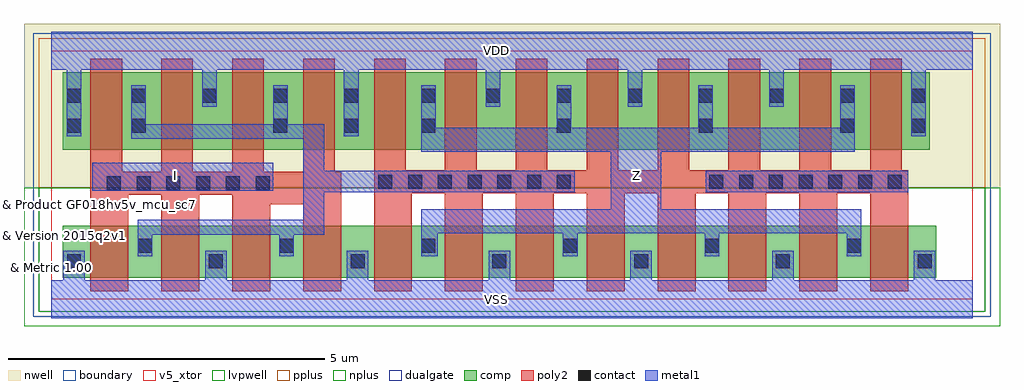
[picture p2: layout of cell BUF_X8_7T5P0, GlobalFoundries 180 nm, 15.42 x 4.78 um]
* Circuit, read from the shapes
.subckt BUF_X8_7T5P0 I VDD VSS Z
XM1 n1 I VSS VSUBS nfet_05v0 w=0.82u l=0.6u m=4
XM2 Z n1 VSS VSUBS nfet_05v0 w=0.82u l=0.6u m=8
XM3 n1 I VDD n2 pfet_05v0 w=1.22u l=0.5u m=4
XM4 Z n1 VDD n2 pfet_05v0 w=1.22u l=0.5u m=8
.ends

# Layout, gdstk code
import gdstk
lib = gdstk.Library(unit=1e-6, precision=1e-09)
def R(c, l, rs):  # rectangles x0, y0, x1, y1
    for r in rs: c.add(gdstk.rectangle(r[:2], r[2:], *l))
def A(c, l, x, y, w, h, nx, ny, dx, dy):  # array of equal rectangles
    R(c, l, [(x+i*dx, y+j*dy, x+i*dx+w, y+j*dy+h) for i in range(nx) for j in range(ny)])
def P(c, l, *ps):  # polygons
    for p in ps: c.add(gdstk.Polygon(p, *l))
boundary = (0, 0)
nwell = (21, 0)
comp = (22, 0)
poly2 = (30, 0)
pplus = (31, 0)
nplus = (32, 0)
contact = (33, 0)
metal1 = (34, 0)
dualgate = (55, 0)
v5_xtor = (112, 1)
lvpwell = (204, 0)

buf_x8_7t5p0 = lib.new_cell('BUF_X8_7T5P0')
R(buf_x8_7t5p0, boundary, [(0,0,14.56,3.92)])
R(buf_x8_7t5p0, nwell, [(-0.43,1.76,14.99,4.35)])
R(buf_x8_7t5p0, comp, [(0.18,0.34,13.98,1.16), (0.18,2.36,13.88,3.58)])
P(buf_x8_7t5p0, poly2, [(0.62,0.12),(1.22,0.12),(1.22,1.65),(1.74,1.65),(1.74,0.12),(2.34,0.12),(2.34,1.65),(2.86,1.65),(2.86,0.12),(3.46,0.12),(3.46,1.5),(3.98,1.5),(3.98,0.12),(4.58,0.12),(4.58,2.01),(4.48,2.01),(4.48,3.8),(3.98,3.8),(3.98,2.01),(3.36,2.01),(3.36,3.8),(2.86,3.8),(2.86,2.01),(2.24,2.01),(2.24,3.8),(1.74,3.8),(1.74,2.01),(1.12,2.01),(1.12,3.8),(0.62,3.8)],
  [(5.1,0.12),(5.7,0.12),(5.7,1.675),(6.22,1.675),(6.22,0.12),(6.82,0.12),(6.82,1.675),(7.34,1.675),(7.34,0.12),(7.94,0.12),(7.94,1.675),(8.46,1.675),(8.46,0.12),(9.06,0.12),(9.06,1.675),(9.58,1.675),(9.58,0.12),(10.18,0.12),(10.18,1.675),(10.7,1.675),(10.7,0.12),(11.3,0.12),(11.3,1.675),(11.82,1.675),(11.82,0.12),(12.42,0.12),(12.42,1.675),(12.94,1.675),(12.94,0.12),(13.54,0.12),(13.54,2.035),(13.44,2.035),(13.44,3.8),(12.94,3.8),(12.94,2.035),(12.32,2.035),(12.32,3.8),(11.82,3.8),(11.82,2.035),(11.2,2.035),(11.2,3.8),(10.7,3.8),(10.7,2.035),(10.08,2.035),(10.08,3.8),(9.58,3.8),(9.58,2.035),(8.96,2.035),(8.96,3.8),(8.46,3.8),(8.46,2.035),(7.84,2.035),(7.84,3.8),(7.34,3.8),(7.34,2.035),(6.72,2.035),(6.72,3.8),(6.22,3.8),(6.22,2.035),(5.6,2.035),(5.6,3.8),(5.1,3.8)])
R(buf_x8_7t5p0, pplus, [(-0.2,1.76,14.76,4.12)])
R(buf_x8_7t5p0, nplus, [(-0.2,-0.2,14.76,1.76)])
A(buf_x8_7t5p0, contact, 0.25, 0.485, 0.22, 0.22, 7, 1, 2.24, 0)
A(buf_x8_7t5p0, contact, 1.37, 0.735, 0.22, 0.22, 6, 1, 2.24, 0)
A(buf_x8_7t5p0, contact, 0.88, 1.72, 0.22, 0.22, 6, 1, 0.47, 0)
A(buf_x8_7t5p0, contact, 5.17, 1.745, 0.22, 0.22, 7, 1, 0.47, 0)
A(buf_x8_7t5p0, contact, 10.4, 1.745, 0.22, 0.22, 7, 1, 0.47, 0)
A(buf_x8_7t5p0, contact, 7.99, 2.63, 0.22, 0.22, 3, 1, 2.24, 0)
A(buf_x8_7t5p0, contact, 1.27, 3.1, 0.22, 0.22, 4, 1, 1.12, 0)
A(buf_x8_7t5p0, contact, 6.87, 3.1, 0.22, 0.22, 7, 1, 1.12, 0)
R(buf_x8_7t5p0, contact, [(0.25,2.63,0.47,2.85), (1.27,2.63,1.49,2.85), (3.51,2.63,3.73,2.85), (4.63,2.63,4.85,2.85), (5.85,2.63,6.07,2.85), (13.59,2.63,13.81,2.85), (0.25,3.1,0.47,3.32), (5.85,3.1,6.07,3.32)])
R(buf_x8_7t5p0, metal1, [(10.34,1.685,13.54,2.03), (0.65,1.715,3.51,2.15)])
P(buf_x8_7t5p0, metal1, [(1.265,2.53),(3.98,2.53),(3.98,1.25),(1.365,1.25),(1.365,0.675),(1.595,0.675),(1.595,1.015),(3.605,1.015),(3.605,0.675),(3.835,0.675),(3.835,1.015),(4.315,1.015),(4.315,1.685),(8.27,1.685),(8.27,2.025),(4.315,2.025),(4.315,2.76),(3.735,2.76),(3.735,3.38),(3.505,3.38),(3.505,2.76),(1.495,2.76),(1.495,3.38),(1.265,3.38)],
  [(5.845,2.33),(8.84,2.33),(8.84,1.42),(5.845,1.42),(5.845,0.675),(6.105,0.675),(6.105,1.04),(8.085,1.04),(8.085,0.675),(8.315,0.675),(8.315,1.04),(10.325,1.04),(10.325,0.675),(10.555,0.675),(10.555,1.04),(12.565,1.04),(12.565,0.675),(12.795,0.675),(12.795,1.42),(9.64,1.42),(9.64,2.33),(12.695,2.33),(12.695,3.38),(12.465,3.38),(12.465,2.71),(10.455,2.71),(10.455,3.38),(10.225,3.38),(10.225,2.71),(8.215,2.71),(8.215,3.38),(7.985,3.38),(7.985,2.71),(6.075,2.71),(6.075,3.38),(5.845,3.38)],
  [(0,-0.3),(14.56,-0.3),(14.56,0.3),(13.97,0.3),(13.97,0.765),(13.63,0.765),(13.63,0.3),(11.73,0.3),(11.73,0.765),(11.39,0.765),(11.39,0.3),(9.49,0.3),(9.49,0.765),(9.15,0.765),(9.15,0.3),(7.25,0.3),(7.25,0.765),(6.91,0.765),(6.91,0.3),(5.01,0.3),(5.01,0.765),(4.67,0.765),(4.67,0.3),(2.77,0.3),(2.77,0.765),(2.43,0.765),(2.43,0.3),(0.53,0.3),(0.53,0.765),(0.19,0.765),(0.19,0.3),(0,0.3)],
  [(0,3.62),(0.245,3.62),(0.245,2.57),(0.475,2.57),(0.475,3.62),(2.385,3.62),(2.385,3.04),(2.615,3.04),(2.615,3.62),(4.625,3.62),(4.625,2.57),(4.855,2.57),(4.855,3.62),(6.865,3.62),(6.865,3.04),(7.095,3.04),(7.095,3.62),(9.105,3.62),(9.105,3.04),(9.335,3.04),(9.335,3.62),(11.345,3.62),(11.345,3.04),(11.575,3.04),(11.575,3.62),(13.585,3.62),(13.585,2.57),(13.815,2.57),(13.815,3.62),(14.56,3.62),(14.56,4.22),(0,4.22)])
R(buf_x8_7t5p0, dualgate, [(-0.28,-0.28,14.84,4.2)])
R(buf_x8_7t5p0, v5_xtor, [(0,0,14.56,3.92)])
R(buf_x8_7t5p0, lvpwell, [(-0.43,-0.43,14.99,1.76)])
buf_x8_7t5p0.add(gdstk.Label('Z', (9.24,1.96), layer=34, texttype=10))
buf_x8_7t5p0.add(gdstk.Label('I', (1.96,1.96), layer=34, texttype=10))
buf_x8_7t5p0.add(gdstk.Label('VDD', (7.03,3.92), layer=34, texttype=10))
buf_x8_7t5p0.add(gdstk.Label('VSS', (7.03,0), layer=34, texttype=10))
buf_x8_7t5p0.add(gdstk.Label('& Vendor GLOBALFOUNDRIES', (0,2), layer=63, texttype=63))
buf_x8_7t5p0.add(gdstk.Label('& Product GF018hv5v_mcu_sc7', (0,1.5), layer=63, texttype=63))
buf_x8_7t5p0.add(gdstk.Label('& Version 2015q2v1', (0,1), layer=63, texttype=63))
buf_x8_7t5p0.add(gdstk.Label('& Metric 1.00', (0,0.5), layer=63, texttype=63))

lib.write_gds('BUF_X8_7T5P0.gds')
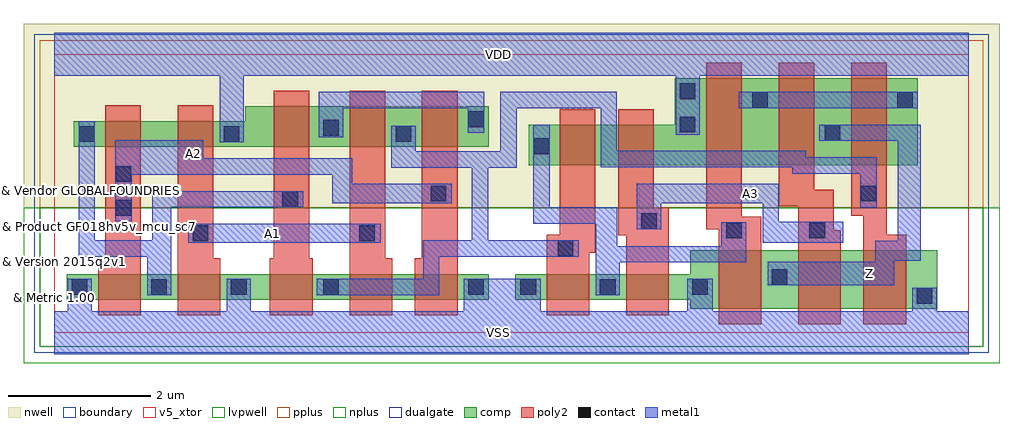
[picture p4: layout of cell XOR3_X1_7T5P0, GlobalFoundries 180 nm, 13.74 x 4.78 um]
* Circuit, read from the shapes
.subckt XOR3_X1_7T5P0 A1 A2 A3 VDD VSS Z
XM1 n1 A2 VSS VSUBS nfet_05v0 w=0.36u l=0.6u
XM2 VSS A1 n1 VSUBS nfet_05v0 w=0.36u l=0.6u
XM3 n2 n1 VSS VSUBS nfet_05v0 w=0.36u l=0.6u
XM4 n3 A1 n2 VSUBS nfet_05v0 w=0.36u l=0.6u
XM5 VSS A2 n3 VSUBS nfet_05v0 w=0.36u l=0.6u
XM6 n4 n2 VSS VSUBS nfet_05v0 w=0.36u l=0.6u
XM7 VSS A3 n4 VSUBS nfet_05v0 w=0.36u l=0.6u
XM8 Z n4 VSS VSUBS nfet_05v0 w=0.82u l=0.6u
XM9 n5 A3 Z VSUBS nfet_05v0 w=0.82u l=0.6u
XM10 VSS n2 n5 VSUBS nfet_05v0 w=0.82u l=0.6u
XM11 n6 A2 n1 n7 pfet_05v0 w=0.36u l=0.5u
XM12 VDD A1 n6 n7 pfet_05v0 w=0.36u l=0.5u
XM13 n8 n1 VDD n7 pfet_05v0 w=0.565u l=0.5u
XM14 n2 A1 n8 n7 pfet_05v0 w=0.565u l=0.5u
XM15 n8 A2 n2 n7 pfet_05v0 w=0.565u l=0.5u
XM16 n9 n2 n4 n7 pfet_05v0 w=0.565u l=0.5u
XM17 VDD A3 n9 n7 pfet_05v0 w=0.565u l=0.5u
XM18 n10 n4 VDD n7 pfet_05v0 w=1.22u l=0.5u
XM19 Z A3 n10 n7 pfet_05v0 w=1.22u l=0.5u
XM20 n10 n2 Z n7 pfet_05v0 w=1.22u l=0.5u
.ends

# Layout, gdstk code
import gdstk
lib = gdstk.Library(unit=1e-6, precision=1e-09)
def R(c, l, rs):  # rectangles x0, y0, x1, y1
    for r in rs: c.add(gdstk.rectangle(r[:2], r[2:], *l))
def A(c, l, x, y, w, h, nx, ny, dx, dy):  # array of equal rectangles
    R(c, l, [(x+i*dx, y+j*dy, x+i*dx+w, y+j*dy+h) for i in range(nx) for j in range(ny)])
def P(c, l, *ps):  # polygons
    for p in ps: c.add(gdstk.Polygon(p, *l))
boundary = (0, 0)
nwell = (21, 0)
comp = (22, 0)
poly2 = (30, 0)
pplus = (31, 0)
nplus = (32, 0)
contact = (33, 0)
metal1 = (34, 0)
dualgate = (55, 0)
v5_xtor = (112, 1)
lvpwell = (204, 0)

xor3_x1_7t5p0 = lib.new_cell('XOR3_X1_7T5P0')
R(xor3_x1_7t5p0, boundary, [(0,0,12.88,3.92)])
R(xor3_x1_7t5p0, nwell, [(-0.43,1.76,13.31,4.35)])
R(xor3_x1_7t5p0, comp, [(0.18,0.465,6.12,0.825)])
P(xor3_x1_7t5p0, comp, [(0.28,2.62),(6.12,2.62),(6.12,3.185),(2.69,3.185),(2.69,2.98),(0.28,2.98)],
  [(6.68,2.36),(12.16,2.36),(12.16,3.58),(8.74,3.58),(8.74,2.925),(6.68,2.925)],
  [(6.495,0.465),(8.955,0.465),(8.955,0.34),(12.435,0.34),(12.435,1.16),(8.955,1.16),(8.955,0.825),(6.495,0.825)])
P(xor3_x1_7t5p0, poly2, [(0.62,0.245),(1.22,0.245),(1.22,3.2),(0.72,3.2),(0.72,1.045),(0.62,1.045)],
  [(1.74,0.245),(2.34,0.245),(2.34,1.045),(2.24,1.045),(2.24,3.2),(1.74,3.2)],
  [(3.04,0.245),(3.64,0.245),(3.64,1.045),(3.59,1.045),(3.59,3.405),(3.09,3.405),(3.09,1.045),(3.04,1.045)],
  [(4.16,0.245),(4.76,0.245),(4.76,1.045),(4.66,1.045),(4.66,3.405),(4.16,3.405)],
  [(5.08,0.245),(5.68,0.245),(5.68,3.405),(5.18,3.405),(5.18,1.045),(5.08,1.045)],
  [(6.935,0.245),(7.535,0.245),(7.535,1.125),(7.62,1.125),(7.62,3.145),(7.12,3.145),(7.12,1.38),(6.935,1.38)],
  [(7.94,1.375),(8.055,1.375),(8.055,0.245),(8.655,0.245),(8.655,1.76),(8.44,1.76),(8.44,3.145),(7.94,3.145)],
  [(9.18,1.46),(9.355,1.46),(9.355,0.12),(9.955,0.12),(9.955,1.63),(9.68,1.63),(9.68,3.8),(9.18,3.8)],
  [(10.2,1.78),(10.475,1.78),(10.475,0.12),(11.075,0.12),(11.075,1.44),(10.975,1.44),(10.975,2.01),(10.7,2.01),(10.7,3.8),(10.2,3.8)],
  [(11.22,1.65),(11.395,1.65),(11.395,0.12),(11.995,0.12),(11.995,1.38),(11.72,1.38),(11.72,3.8),(11.22,3.8)])
R(xor3_x1_7t5p0, pplus, [(-0.2,1.76,13.08,4.12)])
R(xor3_x1_7t5p0, nplus, [(-0.2,-0.2,13.08,1.76)])
A(xor3_x1_7t5p0, contact, 0.25, 0.535, 0.22, 0.22, 3, 1, 1.12, 0)
R(xor3_x1_7t5p0, contact, [(12.145,0.41,12.365,0.63), (3.79,0.535,4.01,0.755), (5.83,0.535,6.05,0.755), (6.565,0.535,6.785,0.755), (7.685,0.535,7.905,0.755), (8.985,0.535,9.205,0.755), (10.105,0.675,10.325,0.895), (7.09,1.08,7.31,1.3), (1.95,1.29,2.17,1.51), (4.295,1.29,4.515,1.51), (9.46,1.33,9.68,1.55), (10.635,1.33,10.855,1.55), (8.265,1.46,8.485,1.68), (0.87,1.65,1.09,1.87), (3.215,1.77,3.435,1.99), (5.3,1.85,5.52,2.07), (11.355,1.85,11.575,2.07), (0.87,2.125,1.09,2.345), (6.75,2.515,6.97,2.735), (0.35,2.69,0.57,2.91), (2.39,2.69,2.61,2.91), (4.81,2.69,5.03,2.91), (10.85,2.705,11.07,2.925), (3.79,2.775,4.01,2.995), (8.81,2.82,9.03,3.04), (5.83,2.895,6.05,3.115), (9.83,3.165,10.05,3.385), (11.87,3.165,12.09,3.385), (8.81,3.29,9.03,3.51)])
R(xor3_x1_7t5p0, metal1, [(1.89,1.265,4.6,1.535), (9.64,3.16,12.16,3.39)])
P(xor3_x1_7t5p0, metal1, [(0.345,1.07),(1.31,1.07),(1.31,0.53),(1.65,0.53),(1.65,1.765),(3.51,1.765),(3.51,1.995),(1.385,1.995),(1.385,1.305),(0.575,1.305),(0.575,2.98),(0.345,2.98)],
  [(0.865,1.57),(1.095,1.57),(1.095,2.225),(3.915,2.225),(3.915,1.82),(5.6,1.82),(5.6,2.095),(4.195,2.095),(4.195,2.455),(2.1,2.455),(2.1,2.71),(0.865,2.71)],
  [(3.73,2.755),(4.07,2.755),(4.07,3.16),(5.825,3.16),(5.825,2.815),(6.055,2.815),(6.055,3.39),(3.73,3.39)],
  [(6.745,1.535),(7.625,1.535),(7.625,0.53),(7.965,0.53),(7.965,0.99),(9.745,0.99),(9.745,1.555),(9.395,1.555),(9.395,1.22),(7.93,1.22),(7.93,1.765),(6.975,1.765),(6.975,2.925),(6.745,2.925)],
  [(8.205,1.455),(8.545,1.455),(8.545,1.825),(9.975,1.825),(9.975,1.265),(11.11,1.265),(11.11,1.56),(10.205,1.56),(10.205,2.1),(8.205,2.1)],
  [(6.11,2.325),(6.515,2.325),(6.515,3.16),(7.695,3.16),(7.695,2.33),(10.395,2.33),(10.395,2.24),(11.35,2.24),(11.35,1.76),(11.585,1.76),(11.585,2.47),(10.585,2.47),(10.585,2.56),(7.925,2.56),(7.925,3.39),(6.285,3.39),(6.285,2.555),(5.09,2.555),(5.09,2.915),(4.75,2.915),(4.75,2.325),(5.88,2.325),(5.88,1.305),(5.195,1.305),(5.195,0.76),(3.7,0.76),(3.7,0.53),(5.425,0.53),(5.425,1.07),(7.39,1.07),(7.39,1.305),(6.11,1.305)],
  [(10.77,2.7),(11.88,2.7),(11.88,1.295),(11.56,1.295),(11.56,1),(10.045,1),(10.045,0.67),(11.83,0.67),(11.83,1.015),(12.2,1.015),(12.2,2.93),(10.77,2.93)],
  [(0,-0.3),(12.88,-0.3),(12.88,0.3),(12.425,0.3),(12.425,0.635),(12.085,0.635),(12.085,0.3),(9.275,0.3),(9.275,0.76),(8.915,0.76),(8.915,0.3),(6.85,0.3),(6.85,0.76),(5.77,0.76),(5.77,0.3),(2.77,0.3),(2.77,0.76),(2.43,0.76),(2.43,0.3),(0.53,0.3),(0.53,0.76),(0.19,0.76),(0.19,0.3),(0,0.3)],
  [(0,3.62),(2.33,3.62),(2.33,2.685),(2.67,2.685),(2.67,3.62),(8.75,3.62),(8.75,2.79),(9.09,2.79),(9.09,3.62),(12.88,3.62),(12.88,4.22),(0,4.22)])
R(xor3_x1_7t5p0, dualgate, [(-0.28,-0.28,13.16,4.2)])
R(xor3_x1_7t5p0, v5_xtor, [(0,0,12.88,3.92)])
R(xor3_x1_7t5p0, lvpwell, [(-0.43,-0.43,13.31,1.76)])
xor3_x1_7t5p0.add(gdstk.Label('A3', (9.8,1.96), layer=34, texttype=10))
xor3_x1_7t5p0.add(gdstk.Label('VDD', (6.255,3.92), layer=34, texttype=10))
xor3_x1_7t5p0.add(gdstk.Label('VSS', (6.26,0), layer=34, texttype=10))
xor3_x1_7t5p0.add(gdstk.Label('Z', (11.48,0.84), layer=34, texttype=10))
xor3_x1_7t5p0.add(gdstk.Label('A1', (3.08,1.4), layer=34, texttype=10))
xor3_x1_7t5p0.add(gdstk.Label('A2', (1.96,2.52), layer=34, texttype=10))
xor3_x1_7t5p0.add(gdstk.Label('& Vendor GLOBALFOUNDRIES', (0,2), layer=63, texttype=63))
xor3_x1_7t5p0.add(gdstk.Label('& Product GF018hv5v_mcu_sc7', (0,1.5), layer=63, texttype=63))
xor3_x1_7t5p0.add(gdstk.Label('& Version 2015q2v1', (0,1), layer=63, texttype=63))
xor3_x1_7t5p0.add(gdstk.Label('& Metric 1.00', (0,0.5), layer=63, texttype=63))

lib.write_gds('XOR3_X1_7T5P0.gds')
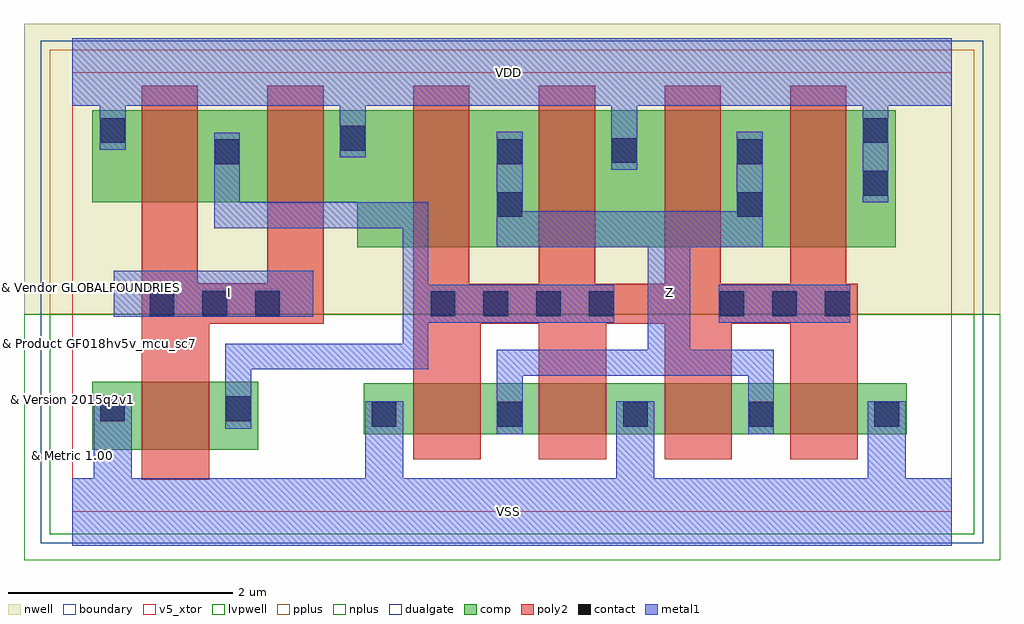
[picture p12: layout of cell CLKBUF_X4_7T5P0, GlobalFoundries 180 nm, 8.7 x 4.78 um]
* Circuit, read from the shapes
.subckt CLKBUF_X4_7T5P0 I VDD VSS Z
XM1 n1 I VSS VSUBS nfet_05v0 w=0.605u l=0.6u
XM2 Z n1 VSS VSUBS nfet_05v0 w=0.455u l=0.6u m=4
XM3 n1 I VDD n2 pfet_05v0 w=0.82u l=0.5u m=2
XM4 Z n1 VDD n2 pfet_05v0 w=1.22u l=0.5u m=4
.ends

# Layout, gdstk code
import gdstk
lib = gdstk.Library(unit=1e-6, precision=1e-09)
def R(c, l, rs):  # rectangles x0, y0, x1, y1
    for r in rs: c.add(gdstk.rectangle(r[:2], r[2:], *l))
def A(c, l, x, y, w, h, nx, ny, dx, dy):  # array of equal rectangles
    R(c, l, [(x+i*dx, y+j*dy, x+i*dx+w, y+j*dy+h) for i in range(nx) for j in range(ny)])
def P(c, l, *ps):  # polygons
    for p in ps: c.add(gdstk.Polygon(p, *l))
boundary = (0, 0)
nwell = (21, 0)
comp = (22, 0)
poly2 = (30, 0)
pplus = (31, 0)
nplus = (32, 0)
contact = (33, 0)
metal1 = (34, 0)
dualgate = (55, 0)
v5_xtor = (112, 1)
lvpwell = (204, 0)

clkbuf_x4_7t5p0 = lib.new_cell('CLKBUF_X4_7T5P0')
R(clkbuf_x4_7t5p0, boundary, [(0,0,7.84,3.92)])
R(clkbuf_x4_7t5p0, nwell, [(-0.43,1.76,8.27,4.35)])
R(clkbuf_x4_7t5p0, comp, [(0.18,0.555,1.66,1.16), (2.6,0.69,7.44,1.145)])
P(clkbuf_x4_7t5p0, comp, [(0.18,2.76),(2.54,2.76),(2.54,2.36),(7.34,2.36),(7.34,3.58),(0.18,3.58)])
P(clkbuf_x4_7t5p0, poly2, [(0.62,0.285),(1.22,0.285),(1.22,1.675),(2.24,1.675),(2.24,3.8),(1.74,3.8),(1.74,2.04),(1.12,2.04),(1.12,3.8),(0.62,3.8)],
  [(3.04,0.47),(3.64,0.47),(3.64,1.675),(4.16,1.675),(4.16,0.47),(4.76,0.47),(4.76,1.675),(5.28,1.675),(5.28,0.47),(5.88,0.47),(5.88,1.675),(6.4,1.675),(6.4,0.47),(7,0.47),(7,2.035),(6.9,2.035),(6.9,3.8),(6.4,3.8),(6.4,2.035),(5.78,2.035),(5.78,3.8),(5.28,3.8),(5.28,2.035),(4.66,2.035),(4.66,3.8),(4.16,3.8),(4.16,2.035),(3.54,2.035),(3.54,3.8),(3.04,3.8)])
R(clkbuf_x4_7t5p0, pplus, [(-0.2,1.76,8.04,4.12)])
R(clkbuf_x4_7t5p0, nplus, [(-0.2,-0.2,8.04,1.76)])
A(clkbuf_x4_7t5p0, contact, 2.67, 0.76, 0.22, 0.22, 5, 1, 1.12, 0)
A(clkbuf_x4_7t5p0, contact, 3.195, 1.745, 0.22, 0.22, 4, 1, 0.47, 0)
A(clkbuf_x4_7t5p0, contact, 5.77, 1.745, 0.22, 0.22, 3, 1, 0.47, 0)
A(clkbuf_x4_7t5p0, contact, 0.69, 1.75, 0.22, 0.22, 3, 1, 0.47, 0)
R(clkbuf_x4_7t5p0, contact, [(0.25,0.81,0.47,1.03), (1.37,0.81,1.59,1.03), (3.79,2.63,4.01,2.85), (5.93,2.63,6.15,2.85), (7.05,2.82,7.27,3.04), (1.27,3.1,1.49,3.32), (3.79,3.1,4.01,3.32), (5.93,3.1,6.15,3.32), (4.81,3.11,5.03,3.33), (2.39,3.22,2.61,3.44), (0.25,3.29,0.47,3.51), (7.05,3.29,7.27,3.51)])
R(clkbuf_x4_7t5p0, metal1, [(5.765,1.685,6.935,2.025), (0.37,1.74,2.15,2.15)])
P(clkbuf_x4_7t5p0, metal1, [(1.265,2.53),(2.945,2.53),(2.945,1.5),(1.365,1.5),(1.365,0.74),(1.595,0.74),(1.595,1.27),(3.175,1.27),(3.175,1.685),(4.83,1.685),(4.83,2.025),(3.175,2.025),(3.175,2.76),(1.495,2.76),(1.495,3.38),(1.265,3.38)],
  [(3.785,2.36),(5.13,2.36),(5.13,1.445),(3.785,1.445),(3.785,0.69),(4.015,0.69),(4.015,1.215),(6.025,1.215),(6.025,0.69),(6.255,0.69),(6.255,1.445),(5.51,1.445),(5.51,2.36),(6.155,2.36),(6.155,3.39),(5.925,3.39),(5.925,2.68),(4.015,2.68),(4.015,3.39),(3.785,3.39)],
  [(0,-0.3),(7.84,-0.3),(7.84,0.3),(7.43,0.3),(7.43,0.985),(7.09,0.985),(7.09,0.3),(5.19,0.3),(5.19,0.985),(4.85,0.985),(4.85,0.3),(2.95,0.3),(2.95,0.985),(2.61,0.985),(2.61,0.3),(0.53,0.3),(0.53,1.04),(0.19,1.04),(0.19,0.3),(0,0.3)],
  [(0,3.62),(0.245,3.62),(0.245,3.23),(0.475,3.23),(0.475,3.62),(2.385,3.62),(2.385,3.16),(2.615,3.16),(2.615,3.62),(4.805,3.62),(4.805,3.05),(5.035,3.05),(5.035,3.62),(7.045,3.62),(7.045,2.76),(7.275,2.76),(7.275,3.62),(7.84,3.62),(7.84,4.22),(0,4.22)])
R(clkbuf_x4_7t5p0, dualgate, [(-0.28,-0.28,8.12,4.2)])
R(clkbuf_x4_7t5p0, v5_xtor, [(0,0,7.84,3.92)])
R(clkbuf_x4_7t5p0, lvpwell, [(-0.43,-0.43,8.27,1.76)])
clkbuf_x4_7t5p0.add(gdstk.Label('Z', (5.32,1.96), layer=34, texttype=10))
clkbuf_x4_7t5p0.add(gdstk.Label('VSS', (3.89,0), layer=34, texttype=10))
clkbuf_x4_7t5p0.add(gdstk.Label('VDD', (3.89,3.92), layer=34, texttype=10))
clkbuf_x4_7t5p0.add(gdstk.Label('I', (1.4,1.96), layer=34, texttype=10))
clkbuf_x4_7t5p0.add(gdstk.Label('& Vendor GLOBALFOUNDRIES', (0,2), layer=63, texttype=63))
clkbuf_x4_7t5p0.add(gdstk.Label('& Product GF018hv5v_mcu_sc7', (0,1.5), layer=63, texttype=63))
clkbuf_x4_7t5p0.add(gdstk.Label('& Version 2015q2v1', (0,1), layer=63, texttype=63))
clkbuf_x4_7t5p0.add(gdstk.Label('& Metric 1.00', (0,0.5), layer=63, texttype=63))

lib.write_gds('CLKBUF_X4_7T5P0.gds')
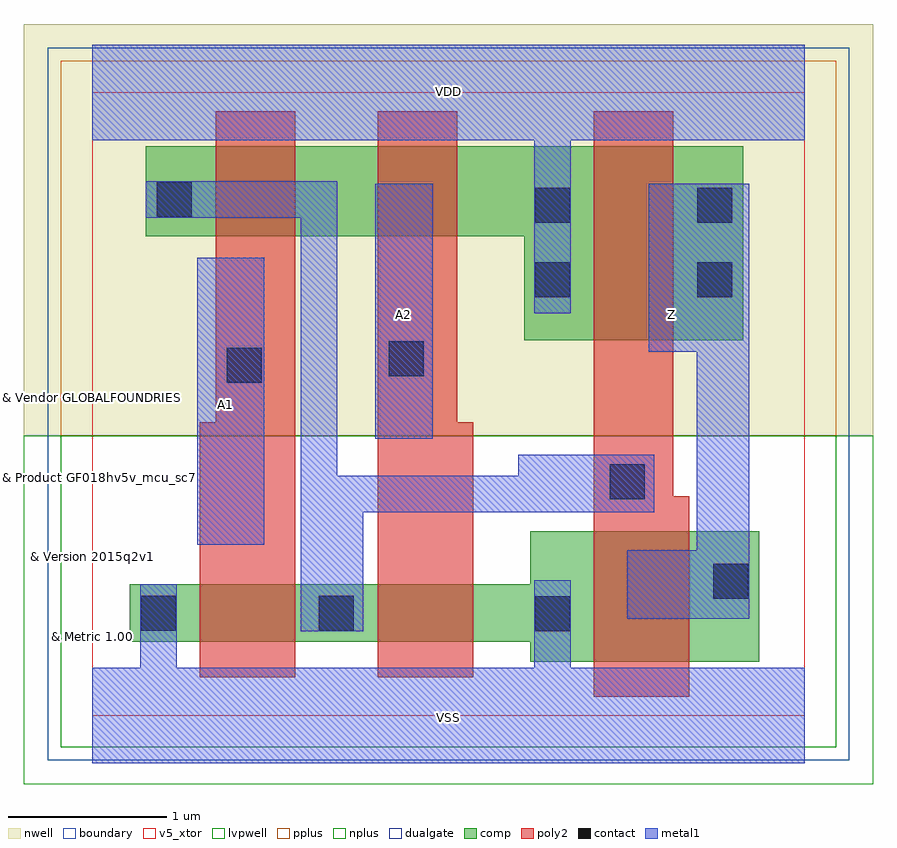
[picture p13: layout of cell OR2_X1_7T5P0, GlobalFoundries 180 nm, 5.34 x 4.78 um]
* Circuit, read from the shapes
.subckt OR2_X1_7T5P0 A1 A2 VDD VSS Z
XM1 n1 A1 VSS VSUBS nfet_05v0 w=0.36u l=0.6u
XM2 VSS A2 n1 VSUBS nfet_05v0 w=0.36u l=0.6u
XM3 Z n1 VSS VSUBS nfet_05v0 w=0.82u l=0.6u
XM4 n2 A1 n1 n3 pfet_05v0 w=0.565u l=0.5u
XM5 VDD A2 n2 n3 pfet_05v0 w=0.565u l=0.5u
XM6 Z n1 VDD n3 pfet_05v0 w=1.22u l=0.5u
.ends

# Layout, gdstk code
import gdstk
lib = gdstk.Library(unit=1e-6, precision=1e-09)
def R(c, l, rs):  # rectangles x0, y0, x1, y1
    for r in rs: c.add(gdstk.rectangle(r[:2], r[2:], *l))
def P(c, l, *ps):  # polygons
    for p in ps: c.add(gdstk.Polygon(p, *l))
boundary = (0, 0)
nwell = (21, 0)
comp = (22, 0)
poly2 = (30, 0)
pplus = (31, 0)
nplus = (32, 0)
contact = (33, 0)
metal1 = (34, 0)
dualgate = (55, 0)
v5_xtor = (112, 1)
lvpwell = (204, 0)

or2_x1_7t5p0 = lib.new_cell('OR2_X1_7T5P0')
R(or2_x1_7t5p0, boundary, [(0,0,4.48,3.92)])
R(or2_x1_7t5p0, nwell, [(-0.43,1.76,4.91,4.35)])
P(or2_x1_7t5p0, comp, [(0.335,3.015),(2.715,3.015),(2.715,2.36),(4.095,2.36),(4.095,3.58),(0.335,3.58)],
  [(0.235,0.465),(2.755,0.465),(2.755,0.34),(4.195,0.34),(4.195,1.16),(2.755,1.16),(2.755,0.825),(0.235,0.825)])
P(or2_x1_7t5p0, poly2, [(0.675,0.24),(1.275,0.24),(1.275,3.8),(0.775,3.8),(0.775,1.845),(0.675,1.845)],
  [(1.795,0.24),(2.395,0.24),(2.395,1.845),(2.295,1.845),(2.295,3.8),(1.795,3.8)],
  [(3.155,0.12),(3.755,0.12),(3.755,1.38),(3.655,1.38),(3.655,3.8),(3.155,3.8)])
R(or2_x1_7t5p0, pplus, [(-0.2,1.76,4.68,4.12)])
R(or2_x1_7t5p0, nplus, [(-0.2,-0.2,4.68,1.76)])
R(or2_x1_7t5p0, contact, [(2.785,0.53,3.005,0.75), (0.305,0.535,0.525,0.755), (1.425,0.535,1.645,0.755), (3.905,0.735,4.125,0.955), (3.255,1.36,3.475,1.58), (0.845,2.095,1.065,2.315), (1.865,2.135,2.085,2.355), (2.785,2.63,3.005,2.85), (3.805,2.63,4.025,2.85), (2.785,3.1,3.005,3.32), (3.805,3.1,4.025,3.32), (0.405,3.135,0.625,3.355)])
R(or2_x1_7t5p0, metal1, [(0.66,1.075,1.08,2.88), (1.78,1.74,2.14,3.345)])
P(or2_x1_7t5p0, metal1, [(0.335,3.13),(1.31,3.13),(1.31,0.53),(1.705,0.53),(1.705,1.28),(3.535,1.28),(3.535,1.64),(2.68,1.64),(2.68,1.51),(1.54,1.51),(1.54,3.36),(0.335,3.36)],
  [(3.5,2.29),(3.8,2.29),(3.8,1.04),(3.365,1.04),(3.365,0.61),(4.13,0.61),(4.13,3.345),(3.5,3.345)],
  [(0,-0.3),(4.48,-0.3),(4.48,0.3),(3.01,0.3),(3.01,0.85),(2.78,0.85),(2.78,0.3),(0.53,0.3),(0.53,0.825),(0.3,0.825),(0.3,0.3),(0,0.3)],
  [(0,3.62),(2.78,3.62),(2.78,2.53),(3.01,2.53),(3.01,3.62),(4.48,3.62),(4.48,4.22),(0,4.22)])
R(or2_x1_7t5p0, dualgate, [(-0.28,-0.28,4.76,4.2)])
R(or2_x1_7t5p0, v5_xtor, [(0,0,4.48,3.92)])
R(or2_x1_7t5p0, lvpwell, [(-0.43,-0.43,4.91,1.76)])
or2_x1_7t5p0.add(gdstk.Label('VDD', (2.24,3.925), layer=34, texttype=10))
or2_x1_7t5p0.add(gdstk.Label('VSS', (2.24,-0.01), layer=34, texttype=10))
or2_x1_7t5p0.add(gdstk.Label('Z', (3.64,2.52), layer=34, texttype=10))
or2_x1_7t5p0.add(gdstk.Label('A1', (0.84,1.96), layer=34, texttype=10))
or2_x1_7t5p0.add(gdstk.Label('A2', (1.96,2.52), layer=34, texttype=10))
or2_x1_7t5p0.add(gdstk.Label('& Vendor GLOBALFOUNDRIES', (0,2), layer=63, texttype=63))
or2_x1_7t5p0.add(gdstk.Label('& Product GF018hv5v_mcu_sc7', (0,1.5), layer=63, texttype=63))
or2_x1_7t5p0.add(gdstk.Label('& Version 2015q2v1', (0,1), layer=63, texttype=63))
or2_x1_7t5p0.add(gdstk.Label('& Metric 1.00', (0,0.5), layer=63, texttype=63))

lib.write_gds('OR2_X1_7T5P0.gds')
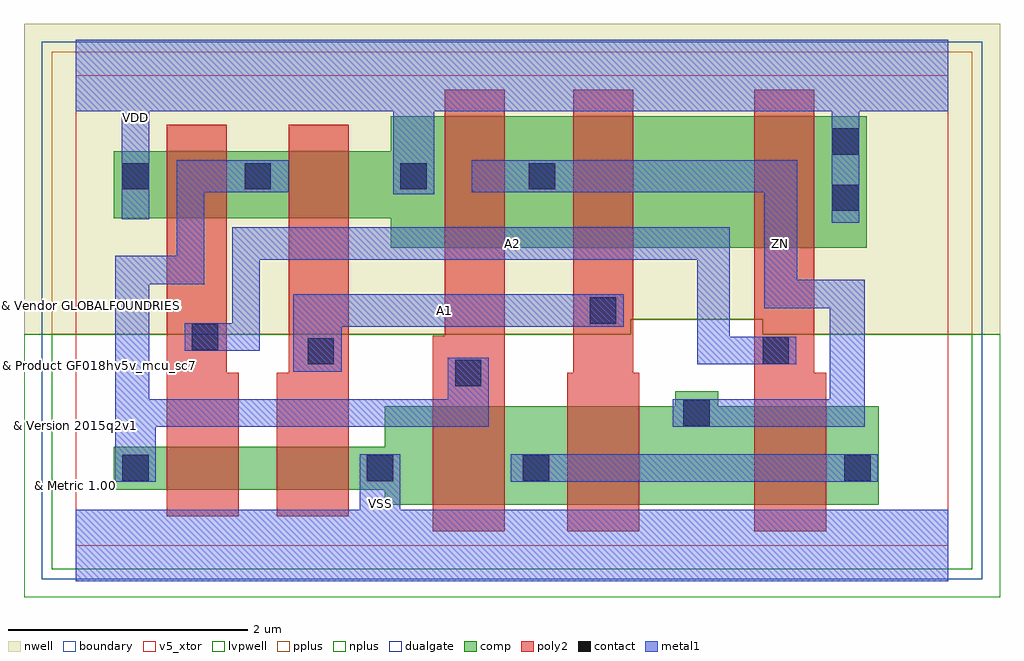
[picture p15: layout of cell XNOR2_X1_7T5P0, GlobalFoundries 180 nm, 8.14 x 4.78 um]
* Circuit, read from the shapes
.subckt XNOR2_X1_7T5P0 A1 A2 VDD VSS ZN
XM1 n1 A2 n2 VSUBS nfet_05v0 w=0.36u l=0.6u
XM2 VSS A1 n1 VSUBS nfet_05v0 w=0.36u l=0.6u
XM3 n3 n2 VSS VSUBS nfet_05v0 w=0.82u l=0.6u
XM4 ZN A1 n3 VSUBS nfet_05v0 w=0.82u l=0.6u
XM5 n3 A2 ZN VSUBS nfet_05v0 w=0.82u l=0.6u
XM6 n2 A2 VDD n4 pfet_05v0 w=0.56u l=0.5u
XM7 VDD A1 n2 n4 pfet_05v0 w=0.56u l=0.5u
XM8 ZN n2 VDD n4 pfet_05v0 w=1.095u l=0.5u
XM9 n5 A1 ZN n4 pfet_05v0 w=1.095u l=0.5u
XM10 VDD A2 n5 n4 pfet_05v0 w=1.095u l=0.5u
.ends

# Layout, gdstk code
import gdstk
lib = gdstk.Library(unit=1e-6, precision=1e-09)
def R(c, l, rs):  # rectangles x0, y0, x1, y1
    for r in rs: c.add(gdstk.rectangle(r[:2], r[2:], *l))
def P(c, l, *ps):  # polygons
    for p in ps: c.add(gdstk.Polygon(p, *l))
boundary = (0, 0)
nwell = (21, 0)
comp = (22, 0)
poly2 = (30, 0)
pplus = (31, 0)
nplus = (32, 0)
contact = (33, 0)
metal1 = (34, 0)
dualgate = (55, 0)
v5_xtor = (112, 1)
lvpwell = (204, 0)

xnor2_x1_7t5p0 = lib.new_cell('XNOR2_X1_7T5P0')
R(xnor2_x1_7t5p0, boundary, [(0,0,7.28,3.92)])
P(xnor2_x1_7t5p0, nwell, [(-0.43,1.76),(4.63,1.76),(4.63,1.885),(5.73,1.885),(5.73,1.76),(7.71,1.76),(7.71,4.35),(-0.43,4.35)])
P(xnor2_x1_7t5p0, comp, [(0.32,2.73),(2.63,2.73),(2.63,2.485),(6.6,2.485),(6.6,3.58),(2.63,3.58),(2.63,3.29),(0.32,3.29)],
  [(0.32,0.465),(2.58,0.465),(2.58,0.34),(6.7,0.34),(6.7,1.16),(5.36,1.16),(5.36,1.285),(5,1.285),(5,1.16),(2.58,1.16),(2.58,0.825),(0.32,0.825)])
P(xnor2_x1_7t5p0, poly2, [(0.76,0.245),(1.36,0.245),(1.36,1.44),(1.26,1.44),(1.26,3.51),(0.76,3.51)],
  [(1.68,0.245),(2.28,0.245),(2.28,3.51),(1.78,3.51),(1.78,1.44),(1.68,1.44)],
  [(2.98,0.12),(3.58,0.12),(3.58,3.8),(3.08,3.8),(3.08,1.75),(2.98,1.75)],
  [(4.1,0.12),(4.7,0.12),(4.7,1.44),(4.65,1.44),(4.65,3.8),(4.15,3.8),(4.15,1.44),(4.1,1.44)],
  [(5.66,0.12),(6.26,0.12),(6.26,1.44),(6.16,1.44),(6.16,3.8),(5.66,3.8)])
P(xnor2_x1_7t5p0, pplus, [(-0.2,1.76),(4.63,1.76),(4.63,1.885),(5.73,1.885),(5.73,1.76),(7.48,1.76),(7.48,4.12),(-0.2,4.12)])
P(xnor2_x1_7t5p0, nplus, [(-0.2,-0.2),(7.48,-0.2),(7.48,1.76),(5.73,1.76),(5.73,1.885),(4.63,1.885),(4.63,1.76),(-0.2,1.76)])
R(xnor2_x1_7t5p0, contact, [(0.39,0.535,0.61,0.755), (2.43,0.535,2.65,0.755), (3.73,0.535,3.95,0.755), (6.41,0.535,6.63,0.755), (5.07,0.995,5.29,1.215), (3.165,1.33,3.385,1.55), (1.935,1.51,2.155,1.73), (5.73,1.515,5.95,1.735), (0.97,1.63,1.19,1.85), (4.29,1.85,4.51,2.07), (6.31,2.79,6.53,3.01), (0.39,2.97,0.61,3.19), (1.41,2.97,1.63,3.19), (2.71,2.97,2.93,3.19), (3.78,2.97,4,3.19), (6.31,3.26,6.53,3.48)])
R(xnor2_x1_7t5p0, metal1, [(3.63,0.53,6.69,0.76)])
P(xnor2_x1_7t5p0, metal1, [(0.33,0.53),(0.67,0.53),(0.67,0.99),(3.445,0.99),(3.445,1.565),(3.105,1.565),(3.105,1.22),(0.615,1.22),(0.615,2.18),(1.075,2.18),(1.075,2.945),(1.78,2.945),(1.78,3.215),(0.845,3.215),(0.845,2.415),(0.33,2.415)],
  [(1.815,1.45),(2.22,1.45),(2.22,1.825),(4.57,1.825),(4.57,2.095),(1.815,2.095)],
  [(0.91,1.625),(1.535,1.625),(1.535,2.385),(5.185,2.385),(5.185,1.51),(6.01,1.51),(6.01,1.74),(5.455,1.74),(5.455,2.655),(1.305,2.655),(1.305,1.855),(0.91,1.855)],
  [(3.305,2.945),(5.745,2.945),(5.745,1.98),(6.29,1.98),(6.29,1.22),(4.98,1.22),(4.98,0.99),(6.58,0.99),(6.58,2.215),(6.02,2.215),(6.02,3.215),(3.305,3.215)],
  [(0,-0.3),(7.28,-0.3),(7.28,0.3),(2.71,0.3),(2.71,0.76),(2.37,0.76),(2.37,0.3),(0,0.3)],
  [(0,3.62),(0.385,3.62),(0.385,2.72),(0.615,2.72),(0.615,3.62),(2.65,3.62),(2.65,2.93),(2.99,2.93),(2.99,3.62),(6.305,3.62),(6.305,2.69),(6.535,2.69),(6.535,3.62),(7.28,3.62),(7.28,4.22),(0,4.22)])
R(xnor2_x1_7t5p0, dualgate, [(-0.28,-0.28,7.56,4.2)])
R(xnor2_x1_7t5p0, v5_xtor, [(0,0,7.28,3.92)])
P(xnor2_x1_7t5p0, lvpwell, [(-0.43,-0.43),(7.71,-0.43),(7.71,1.76),(5.73,1.76),(5.73,1.885),(4.63,1.885),(4.63,1.76),(-0.43,1.76)])
xnor2_x1_7t5p0.add(gdstk.Label('VDD', (0.5,3.57), layer=34, texttype=10))
xnor2_x1_7t5p0.add(gdstk.Label('VSS', (2.54,0.35), layer=34, texttype=10))
xnor2_x1_7t5p0.add(gdstk.Label('ZN', (5.88,2.52), layer=34, texttype=10))
xnor2_x1_7t5p0.add(gdstk.Label('A1', (3.08,1.96), layer=34, texttype=10))
xnor2_x1_7t5p0.add(gdstk.Label('A2', (3.64,2.52), layer=34, texttype=10))
xnor2_x1_7t5p0.add(gdstk.Label('& Vendor GLOBALFOUNDRIES', (0,2), layer=63, texttype=63))
xnor2_x1_7t5p0.add(gdstk.Label('& Product GF018hv5v_mcu_sc7', (0,1.5), layer=63, texttype=63))
xnor2_x1_7t5p0.add(gdstk.Label('& Version 2015q2v1', (0,1), layer=63, texttype=63))
xnor2_x1_7t5p0.add(gdstk.Label('& Metric 1.00', (0,0.5), layer=63, texttype=63))

lib.write_gds('XNOR2_X1_7T5P0.gds')
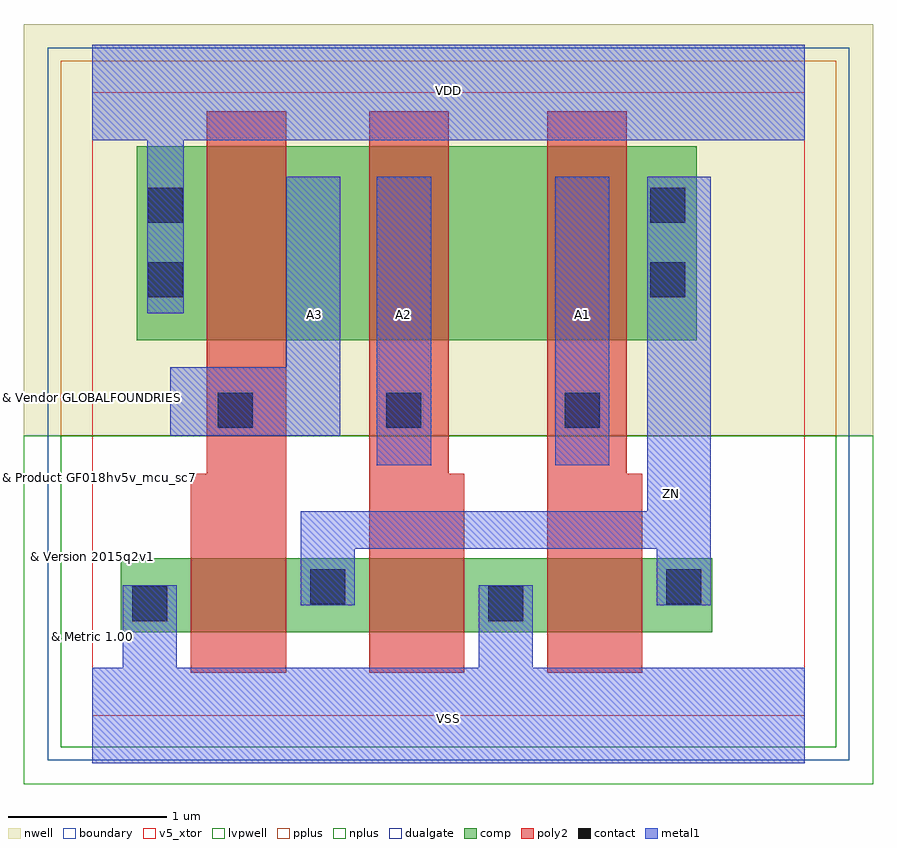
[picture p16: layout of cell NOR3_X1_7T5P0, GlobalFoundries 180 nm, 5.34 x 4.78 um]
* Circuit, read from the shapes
.subckt NOR3_X1_7T5P0 A1 A2 A3 VDD VSS ZN
XM1 ZN A3 VSS VSUBS nfet_05v0 w=0.465u l=0.6u
XM2 VSS A2 ZN VSUBS nfet_05v0 w=0.465u l=0.6u
XM3 ZN A1 VSS VSUBS nfet_05v0 w=0.465u l=0.6u
XM4 n1 A3 VDD n2 pfet_05v0 w=1.22u l=0.5u
XM5 n3 A2 n1 n2 pfet_05v0 w=1.22u l=0.5u
XM6 ZN A1 n3 n2 pfet_05v0 w=1.22u l=0.5u
.ends

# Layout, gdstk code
import gdstk
lib = gdstk.Library(unit=1e-6, precision=1e-09)
def R(c, l, rs):  # rectangles x0, y0, x1, y1
    for r in rs: c.add(gdstk.rectangle(r[:2], r[2:], *l))
def P(c, l, *ps):  # polygons
    for p in ps: c.add(gdstk.Polygon(p, *l))
boundary = (0, 0)
nwell = (21, 0)
comp = (22, 0)
poly2 = (30, 0)
pplus = (31, 0)
nplus = (32, 0)
contact = (33, 0)
metal1 = (34, 0)
dualgate = (55, 0)
v5_xtor = (112, 1)
lvpwell = (204, 0)

nor3_x1_7t5p0 = lib.new_cell('NOR3_X1_7T5P0')
R(nor3_x1_7t5p0, boundary, [(0,0,4.48,3.92)])
R(nor3_x1_7t5p0, nwell, [(-0.43,1.76,4.91,4.35)])
R(nor3_x1_7t5p0, comp, [(0.18,0.525,3.9,0.99), (0.28,2.36,3.8,3.58)])
P(nor3_x1_7t5p0, poly2, [(0.62,0.27),(1.22,0.27),(1.22,3.8),(0.72,3.8),(0.72,1.52),(0.62,1.52)],
  [(1.74,0.27),(2.34,0.27),(2.34,1.52),(2.24,1.52),(2.24,3.8),(1.74,3.8)],
  [(2.86,0.27),(3.46,0.27),(3.46,1.52),(3.36,1.52),(3.36,3.8),(2.86,3.8)])
R(nor3_x1_7t5p0, pplus, [(-0.2,1.76,4.68,4.12)])
R(nor3_x1_7t5p0, nplus, [(-0.2,-0.2,4.68,1.76)])
R(nor3_x1_7t5p0, contact, [(0.25,0.595,0.47,0.815), (2.49,0.595,2.71,0.815), (1.37,0.7,1.59,0.92), (3.61,0.7,3.83,0.92), (0.79,1.81,1.01,2.03), (1.85,1.81,2.07,2.03), (2.97,1.81,3.19,2.03), (0.35,2.63,0.57,2.85), (3.51,2.63,3.73,2.85), (0.35,3.1,0.57,3.32), (3.51,3.1,3.73,3.32)])
R(nor3_x1_7t5p0, metal1, [(1.79,1.575,2.13,3.39), (2.91,1.575,3.25,3.39)])
P(nor3_x1_7t5p0, metal1, [(0.49,1.76),(1.56,1.76),(1.56,3.39),(1.22,3.39),(1.22,2.19),(0.49,2.19)],
  [(1.31,0.695),(1.65,0.695),(1.65,1.05),(3.55,1.05),(3.55,0.695),(3.89,0.695),(3.89,3.39),(3.49,3.39),(3.49,1.285),(1.31,1.285)],
  [(0,-0.3),(4.48,-0.3),(4.48,0.3),(2.77,0.3),(2.77,0.82),(2.43,0.82),(2.43,0.3),(0.53,0.3),(0.53,0.82),(0.19,0.82),(0.19,0.3),(0,0.3)],
  [(0,3.62),(0.345,3.62),(0.345,2.53),(0.575,2.53),(0.575,3.62),(4.48,3.62),(4.48,4.22),(0,4.22)])
R(nor3_x1_7t5p0, dualgate, [(-0.28,-0.28,4.76,4.2)])
R(nor3_x1_7t5p0, v5_xtor, [(0,0,4.48,3.92)])
R(nor3_x1_7t5p0, lvpwell, [(-0.43,-0.43,4.91,1.76)])
nor3_x1_7t5p0.add(gdstk.Label('A3', (1.4,2.52), layer=34, texttype=10))
nor3_x1_7t5p0.add(gdstk.Label('VDD', (2.24,3.93), layer=34, texttype=10))
nor3_x1_7t5p0.add(gdstk.Label('VSS', (2.24,-0.02), layer=34, texttype=10))
nor3_x1_7t5p0.add(gdstk.Label('ZN', (3.64,1.4), layer=34, texttype=10))
nor3_x1_7t5p0.add(gdstk.Label('A1', (3.08,2.52), layer=34, texttype=10))
nor3_x1_7t5p0.add(gdstk.Label('A2', (1.96,2.52), layer=34, texttype=10))
nor3_x1_7t5p0.add(gdstk.Label('& Vendor GLOBALFOUNDRIES', (0,2), layer=63, texttype=63))
nor3_x1_7t5p0.add(gdstk.Label('& Product GF018hv5v_mcu_sc7', (0,1.5), layer=63, texttype=63))
nor3_x1_7t5p0.add(gdstk.Label('& Version 2015q2v1', (0,1), layer=63, texttype=63))
nor3_x1_7t5p0.add(gdstk.Label('& Metric 1.00', (0,0.5), layer=63, texttype=63))

lib.write_gds('NOR3_X1_7T5P0.gds')
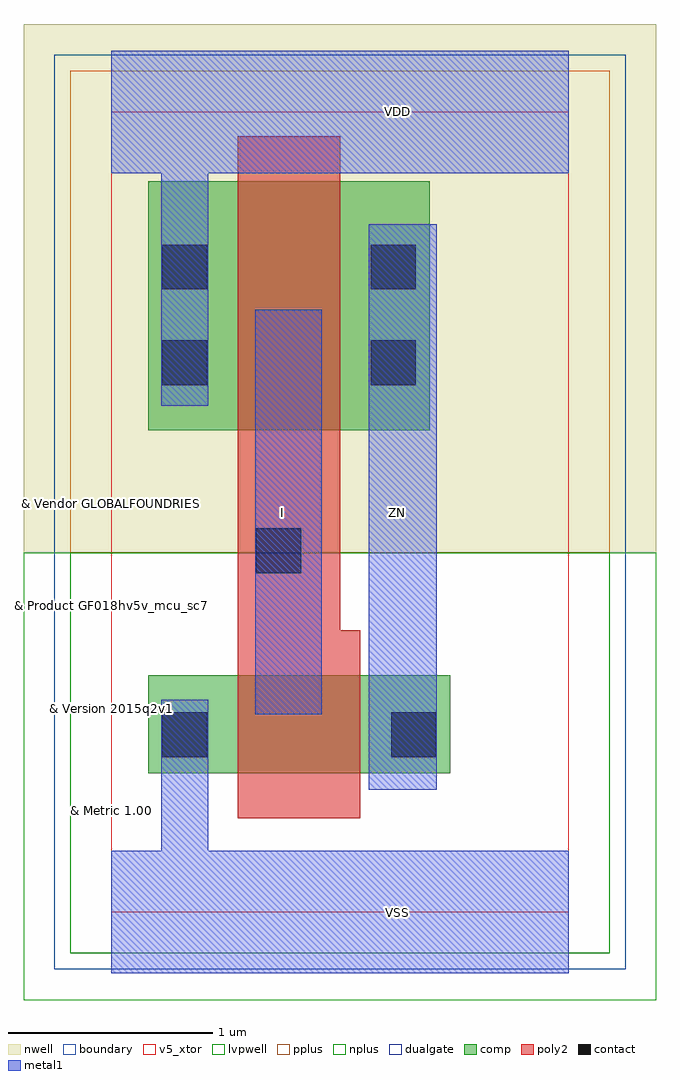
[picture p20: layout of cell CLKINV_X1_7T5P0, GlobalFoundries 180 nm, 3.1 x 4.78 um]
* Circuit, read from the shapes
.subckt CLKINV_X1_7T5P0 I VDD VSS ZN
XM1 ZN I VSS VSUBS nfet_05v0 w=0.48u l=0.6u
XM2 ZN I VDD n1 pfet_05v0 w=1.22u l=0.5u
.ends

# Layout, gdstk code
import gdstk
lib = gdstk.Library(unit=1e-6, precision=1e-09)
def R(c, l, rs):  # rectangles x0, y0, x1, y1
    for r in rs: c.add(gdstk.rectangle(r[:2], r[2:], *l))
def P(c, l, *ps):  # polygons
    for p in ps: c.add(gdstk.Polygon(p, *l))
boundary = (0, 0)
nwell = (21, 0)
comp = (22, 0)
poly2 = (30, 0)
pplus = (31, 0)
nplus = (32, 0)
contact = (33, 0)
metal1 = (34, 0)
dualgate = (55, 0)
v5_xtor = (112, 1)
lvpwell = (204, 0)

clkinv_x1_7t5p0 = lib.new_cell('CLKINV_X1_7T5P0')
R(clkinv_x1_7t5p0, boundary, [(0,0,2.24,3.92)])
R(clkinv_x1_7t5p0, nwell, [(-0.43,1.76,2.67,4.35)])
R(clkinv_x1_7t5p0, comp, [(0.18,0.68,1.66,1.16), (0.18,2.36,1.56,3.58)])
P(clkinv_x1_7t5p0, poly2, [(0.62,0.46),(1.22,0.46),(1.22,1.38),(1.12,1.38),(1.12,3.8),(0.62,3.8)])
R(clkinv_x1_7t5p0, pplus, [(-0.2,1.76,2.44,4.12)])
R(clkinv_x1_7t5p0, nplus, [(-0.2,-0.2,2.44,1.76)])
R(clkinv_x1_7t5p0, contact, [(0.25,0.76,0.47,0.98), (1.37,0.76,1.59,0.98), (0.71,1.66,0.93,1.88), (0.25,2.58,0.47,2.8), (1.27,2.58,1.49,2.8), (0.25,3.05,0.47,3.27), (1.27,3.05,1.49,3.27)])
R(clkinv_x1_7t5p0, metal1, [(1.26,0.6,1.595,3.37), (0.705,0.97,1.03,2.95)])
P(clkinv_x1_7t5p0, metal1, [(0,-0.3),(2.24,-0.3),(2.24,0.3),(0.475,0.3),(0.475,1.04),(0.245,1.04),(0.245,0.3),(0,0.3)],
  [(0,3.62),(0.245,3.62),(0.245,2.48),(0.475,2.48),(0.475,3.62),(2.24,3.62),(2.24,4.22),(0,4.22)])
R(clkinv_x1_7t5p0, dualgate, [(-0.28,-0.28,2.52,4.2)])
R(clkinv_x1_7t5p0, v5_xtor, [(0,0,2.24,3.92)])
R(clkinv_x1_7t5p0, lvpwell, [(-0.43,-0.43,2.67,1.76)])
clkinv_x1_7t5p0.add(gdstk.Label('VDD', (1.4,3.92), layer=34, texttype=10))
clkinv_x1_7t5p0.add(gdstk.Label('VSS', (1.4,0), layer=34, texttype=10))
clkinv_x1_7t5p0.add(gdstk.Label('I', (0.84,1.96), layer=34, texttype=10))
clkinv_x1_7t5p0.add(gdstk.Label('ZN', (1.4,1.96), layer=34, texttype=10))
clkinv_x1_7t5p0.add(gdstk.Label('& Vendor GLOBALFOUNDRIES', (0,2), layer=63, texttype=63))
clkinv_x1_7t5p0.add(gdstk.Label('& Product GF018hv5v_mcu_sc7', (0,1.5), layer=63, texttype=63))
clkinv_x1_7t5p0.add(gdstk.Label('& Version 2015q2v1', (0,1), layer=63, texttype=63))
clkinv_x1_7t5p0.add(gdstk.Label('& Metric 1.00', (0,0.5), layer=63, texttype=63))

lib.write_gds('CLKINV_X1_7T5P0.gds')
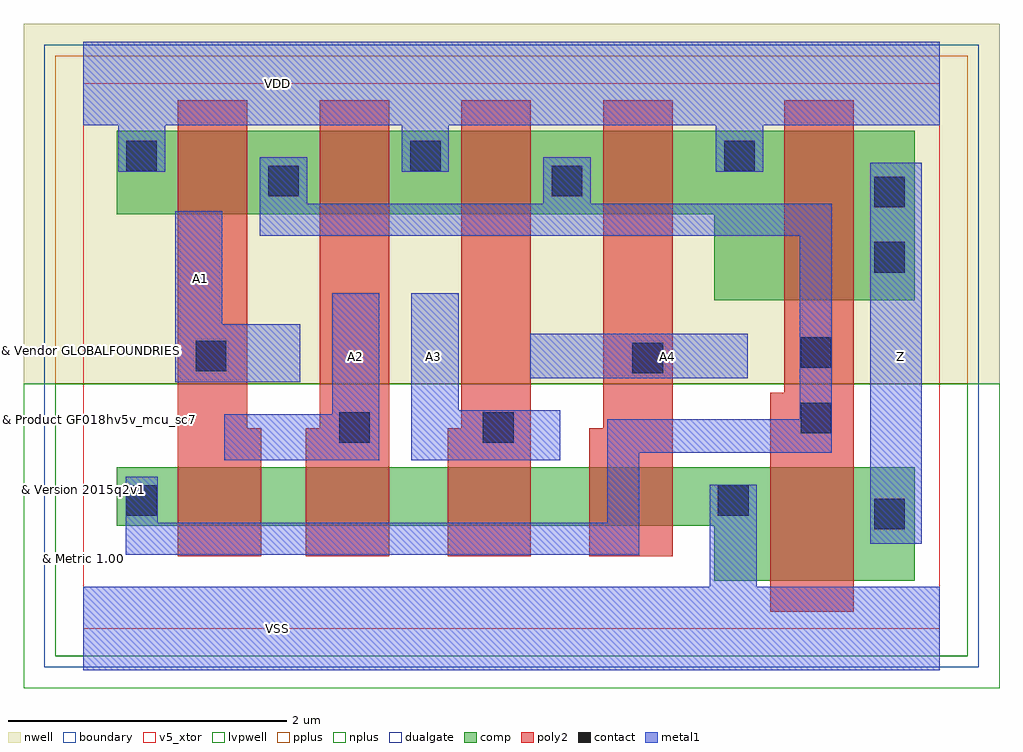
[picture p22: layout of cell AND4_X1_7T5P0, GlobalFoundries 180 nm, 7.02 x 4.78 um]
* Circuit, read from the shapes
.subckt AND4_X1_7T5P0 A1 A2 A3 A4 VDD VSS Z
XM1 n1 A1 n2 VSUBS nfet_05v0 w=0.42u l=0.6u
XM2 n3 A2 n1 VSUBS nfet_05v0 w=0.42u l=0.6u
XM3 n4 A3 n3 VSUBS nfet_05v0 w=0.42u l=0.6u
XM4 VSS A4 n4 VSUBS nfet_05v0 w=0.42u l=0.6u
XM5 Z n2 VSS VSUBS nfet_05v0 w=0.815u l=0.6u
XM6 n2 A1 VDD n5 pfet_05v0 w=0.6u l=0.5u
XM7 VDD A2 n2 n5 pfet_05v0 w=0.6u l=0.5u
XM8 n2 A3 VDD n5 pfet_05v0 w=0.6u l=0.5u
XM9 VDD A4 n2 n5 pfet_05v0 w=0.6u l=0.5u
XM10 Z n2 VDD n5 pfet_05v0 w=1.22u l=0.5u
.ends

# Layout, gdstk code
import gdstk
lib = gdstk.Library(unit=1e-6, precision=1e-09)
def R(c, l, rs):  # rectangles x0, y0, x1, y1
    for r in rs: c.add(gdstk.rectangle(r[:2], r[2:], *l))
def P(c, l, *ps):  # polygons
    for p in ps: c.add(gdstk.Polygon(p, *l))
boundary = (0, 0)
nwell = (21, 0)
comp = (22, 0)
poly2 = (30, 0)
pplus = (31, 0)
nplus = (32, 0)
contact = (33, 0)
metal1 = (34, 0)
dualgate = (55, 0)
v5_xtor = (112, 1)
lvpwell = (204, 0)

and4_x1_7t5p0 = lib.new_cell('AND4_X1_7T5P0')
R(and4_x1_7t5p0, boundary, [(0,0,6.16,3.92)])
R(and4_x1_7t5p0, nwell, [(-0.43,1.76,6.59,4.35)])
P(and4_x1_7t5p0, comp, [(0.24,0.74),(4.54,0.74),(4.54,0.345),(5.98,0.345),(5.98,1.16),(0.24,1.16)],
  [(0.24,2.98),(4.54,2.98),(4.54,2.36),(5.98,2.36),(5.98,3.58),(0.24,3.58)])
P(and4_x1_7t5p0, poly2, [(0.68,0.52),(1.28,0.52),(1.28,1.44),(1.18,1.44),(1.18,3.8),(0.68,3.8)],
  [(1.6,0.52),(2.2,0.52),(2.2,3.8),(1.7,3.8),(1.7,1.44),(1.6,1.44)],
  [(2.62,0.52),(3.22,0.52),(3.22,3.8),(2.72,3.8),(2.72,1.44),(2.62,1.44)],
  [(3.64,0.52),(4.24,0.52),(4.24,3.8),(3.74,3.8),(3.74,1.44),(3.64,1.44)],
  [(4.94,0.12),(5.54,0.12),(5.54,3.8),(5.04,3.8),(5.04,1.695),(4.94,1.695)])
R(and4_x1_7t5p0, pplus, [(-0.2,1.76,6.36,4.12)])
R(and4_x1_7t5p0, nplus, [(-0.2,-0.2,6.36,1.76)])
R(and4_x1_7t5p0, contact, [(5.69,0.715,5.91,0.935), (0.31,0.81,0.53,1.03), (4.565,0.81,4.785,1.03), (1.84,1.335,2.06,1.555), (2.875,1.335,3.095,1.555), (5.16,1.405,5.38,1.625), (3.95,1.835,4.17,2.055), (0.81,1.85,1.03,2.07), (5.16,1.875,5.38,2.095), (5.69,2.56,5.91,2.78), (5.69,3.03,5.91,3.25), (1.33,3.11,1.55,3.33), (3.37,3.11,3.59,3.33), (0.31,3.29,0.53,3.51), (2.35,3.29,2.57,3.51), (4.61,3.29,4.83,3.51)])
R(and4_x1_7t5p0, metal1, [(5.66,0.61,6.03,3.35), (3.215,1.8,4.78,2.12)])
P(and4_x1_7t5p0, metal1, [(0.66,1.77),(1.56,1.77),(1.56,2.19),(1,2.19),(1,3),(0.66,3)],
  [(1.015,1.21),(2.13,1.21),(2.13,2.41),(1.79,2.41),(1.79,1.54),(1.015,1.54)],
  [(2.36,1.21),(3.43,1.21),(3.43,1.57),(2.7,1.57),(2.7,2.41),(2.36,2.41)],
  [(1.27,2.825),(5.155,2.825),(5.155,1.505),(3.77,1.505),(3.77,0.76),(0.535,0.76),(0.535,1.09),(0.305,1.09),(0.305,0.53),(4,0.53),(4,1.265),(5.385,1.265),(5.385,3.055),(3.65,3.055),(3.65,3.39),(3.31,3.39),(3.31,3.055),(1.61,3.055),(1.61,3.39),(1.27,3.39)],
  [(0,-0.3),(6.16,-0.3),(6.16,0.3),(4.845,0.3),(4.845,1.035),(4.505,1.035),(4.505,0.3),(0,0.3)],
  [(0,3.62),(0.25,3.62),(0.25,3.285),(0.59,3.285),(0.59,3.62),(2.29,3.62),(2.29,3.285),(2.63,3.285),(2.63,3.62),(4.55,3.62),(4.55,3.285),(4.89,3.285),(4.89,3.62),(6.16,3.62),(6.16,4.22),(0,4.22)])
R(and4_x1_7t5p0, dualgate, [(-0.28,-0.28,6.44,4.2)])
R(and4_x1_7t5p0, v5_xtor, [(0,0,6.16,3.92)])
R(and4_x1_7t5p0, lvpwell, [(-0.43,-0.43,6.59,1.76)])
and4_x1_7t5p0.add(gdstk.Label('A3', (2.52,1.96), layer=34, texttype=10))
and4_x1_7t5p0.add(gdstk.Label('A4', (4.2,1.96), layer=34, texttype=10))
and4_x1_7t5p0.add(gdstk.Label('VDD', (1.4,3.92), layer=34, texttype=10))
and4_x1_7t5p0.add(gdstk.Label('VSS', (1.4,0), layer=34, texttype=10))
and4_x1_7t5p0.add(gdstk.Label('Z', (5.88,1.96), layer=34, texttype=10))
and4_x1_7t5p0.add(gdstk.Label('A1', (0.84,2.52), layer=34, texttype=10))
and4_x1_7t5p0.add(gdstk.Label('A2', (1.96,1.96), layer=34, texttype=10))
and4_x1_7t5p0.add(gdstk.Label('& Vendor GLOBALFOUNDRIES', (0,2), layer=63, texttype=63))
and4_x1_7t5p0.add(gdstk.Label('& Product GF018hv5v_mcu_sc7', (0,1.5), layer=63, texttype=63))
and4_x1_7t5p0.add(gdstk.Label('& Version 2015q2v1', (0,1), layer=63, texttype=63))
and4_x1_7t5p0.add(gdstk.Label('& Metric 1.00', (0,0.5), layer=63, texttype=63))

lib.write_gds('AND4_X1_7T5P0.gds')
